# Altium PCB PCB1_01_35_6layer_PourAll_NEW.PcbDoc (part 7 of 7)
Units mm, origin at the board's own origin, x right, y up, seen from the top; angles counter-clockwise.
Board outline 26 x 17.5 mm, 6 copper layers (Top Layer, Layer 1, Layer 2, Layer 3, Layer 4, Bottom Layer), stack 0.816 mm thick; 0 components, 1 nets, 8 pads, 78 vias.

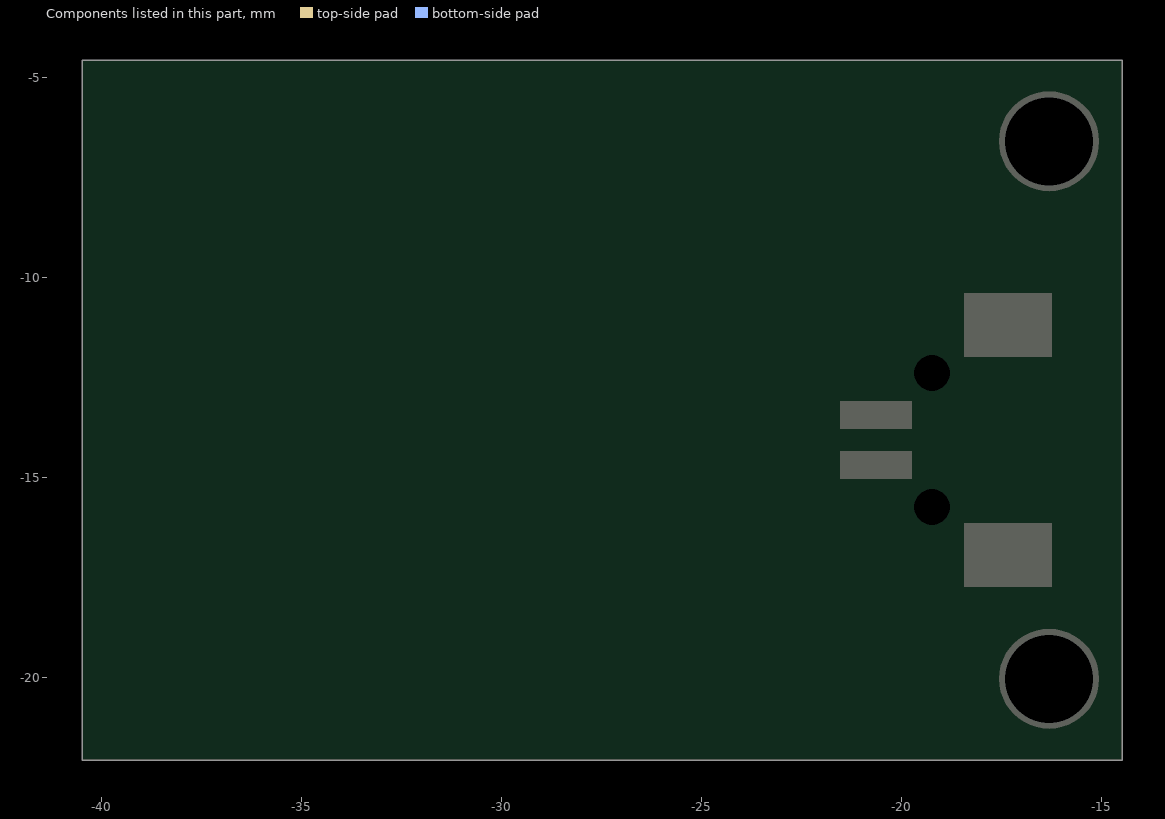
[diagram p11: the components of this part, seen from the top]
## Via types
v1: diameter 0.5, hole 0.3, Top Layer to Bottom Layer, tented both sides, 65 vias
v2: diameter 1, hole 0.5, Top Layer to Bottom Layer, 10 vias
v3: diameter 0.5, hole 0.25, Top Layer to Bottom Layer, 3 vias

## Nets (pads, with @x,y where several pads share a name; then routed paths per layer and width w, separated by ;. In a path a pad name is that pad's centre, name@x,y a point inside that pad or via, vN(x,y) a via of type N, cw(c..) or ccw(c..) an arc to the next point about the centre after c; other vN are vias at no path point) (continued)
copper on no net: (continued)
  Bottom Layer w0.1: -37.134,-9.58 cw(c-31.888,-13.205) -36.202,-8.509 cw(c-31.701,-13.403) -35.061,-7.666 cw(c-31.721,-13.359) -33.768,-7.084 cw(c-31.824,-13.032) -32.381,-6.799 cw(c-31.832,-13.115) -30.968,-6.834 cw(c-31.866,-13.39) -29.596,-7.174 cw(c-31.848,-13.355) -28.329,-7.797 cw(c-31.664,-13.071) -27.231,-8.68 cw(c-31.72,-13.105) -26.361,-9.787 cw(c-31.957,-13.256) -25.751,-11.055 cw(c-31.926,-13.25) -25.425,-12.422 cw(c-31.598,-13.212) -25.405,-13.825 cw(c-31.64,-13.192) -25.702,-15.195 cw(c-31.912,-13.104) -26.288,-16.467 cw(c-31.895,-13.12) -27.13,-17.585 cw(c-31.66,-13.344) -28.194,-18.491 cw(c-31.661,-13.315) -29.433,-19.133 cw(c-31.768,-13.045) -30.781,-19.49 cw(c-31.77,-13.061) -32.173,-19.553 cw(c-31.794,-13.377) -33.543,-19.312 cw(c-31.777,-13.377) -34.822,-18.769 cw(c-31.635,-13.119) -35.951,-17.962 cw(c-31.643,-13.121) -36.883,-16.934 cw(c-31.897,-13.301) -37.568,-15.73 cw(c-31.903,-13.32) -37.963,-14.405 cw(c-31.61,-13.264) -38.06,-13.026 cw(c-31.609,-13.26) -37.863,-11.659 cw(c-31.902,-13.181) -37.374,-10.37 cw(c-31.938,-13.18) -36.608,-9.226 cw(c-31.705,-13.373) -35.612,-8.276 cw(c-31.696,-13.377) -34.438,-7.56 cw(c-31.819,-13.107) -33.139,-7.117 cw(c-31.845,-13.061) -31.775,-6.978 cw(c-31.845,-13.366) -30.415,-7.14 cw(c-31.845,-13.384) -29.121,-7.587 cw(c-31.718,-13.123) -27.956,-8.301 cw(c-31.687,-13.059) -26.984,-9.259 cw(c-31.925,-13.256) -26.245,-10.406 cw(c-31.946,-13.271) -25.767,-11.682 cw(c-31.671,-13.204) -25.576,-13.028 cw(c-31.584,-13.187) -25.694,-14.382 cw(c-31.89,-13.128) -26.105,-15.676 cw(c-31.922,-13.119) -26.78,-16.853 cw(c-31.701,-13.284) -27.692,-17.854 cw(c-31.621,-13.354) -28.805,-18.622 cw(c-31.772,-13.078) -30.058,-19.128 cw(c-31.788,-13.041) -31.389,-19.357 cw(c-31.774,-13.309) -32.735,-19.292 cw(c-31.781,-13.432) -34.031,-18.927 cw(c-31.663,-13.137) -35.214,-18.286 cw(c-31.64,-13.096) -36.234,-17.41 cw(c-31.833,-13.271) -37.039,-16.337 cw(c-31.946,-13.353) -37.581,-15.111 cw(c-31.643,-13.255) -37.84,-13.797 cw(c-31.589,-13.246) -37.815,-12.459 cw(c-31.84,-13.21) -37.503,-11.161 cw(c-31.99,-13.169) -36.906,-9.967 cw(c-31.72,-13.341) -36.063,-8.935 cw(c-31.673,-13.382) -35.021,-8.105 cw(c-31.802,-13.172) -33.827,-7.521 cw(c-31.87,-13.016) -32.533,-7.221 cw(c-31.831,-13.334) -31.206,-7.212 cw(c-31.834,-13.403) -29.909,-7.486 cw(c-31.756,-13.177) -28.703,-8.031 cw(c-31.67,-13.012) -27.652,-8.832 cw(c-31.891,-13.246) -26.804,-9.845 cw(c-31.952,-13.292) -26.19,-11.013 cw(c-31.736,-13.21) -25.843,-12.284 cw(c-31.54,-13.17) -25.791,-13.599 cw(c-31.86,-13.148) -26.029,-14.892 cw(c-31.941,-13.128) -26.537,-16.103 cw(c-31.746,-13.24) -27.291,-17.176 cw(c-31.581,-13.375) -28.266,-18.05 cw(c-31.767,-13.115) -29.409,-18.687 cw(c-31.806,-13.033) -30.66,-19.067 cw(c-31.77,-13.247) -31.961,-19.169 cw(c-31.769,-13.473) -33.25,-18.976 cw(c-31.663,-13.102) -35.548,-17.785 cw(c-31.784,-13.236) -36.452,-16.852 cw(c-31.968,-13.387) -37.122,-15.741 cw(c-31.613,-13.232) -37.667,-13.223 cw(c-31.782,-13.225) -37.524,-11.938 cw(c-32.027,-13.176) -37.098,-10.719 cw(c-31.682,-13.351) -35.512,-8.704 cw(c-31.776,-13.225) -34.436,-7.998 cw(c-31.899,-12.995) -33.231,-7.552 cw(c-31.814,-13.372) -30.68,-7.49 cw(c-31.779,-13.23) -29.456,-7.868 cw(c-31.676,-12.98) -28.349,-8.508 cw(c-31.912,-13.284) -26.684,-10.426 cw(c-31.64,-13.165) -25.985,-12.858 cw(c-31.905,-13.156) -26.4,-15.352 cw(c-31.65,-13.286) -27.822,-17.431 cw(c-31.803,-13.082) -29.997,-18.694 cw(c-31.744,-13.352) -32.493,-18.922 cw(c-31.685,-13.115) -34.842,-18.056 cw(c-31.85,-13.324) -36.6,-16.287 cw(c-31.638,-13.225) -37.425,-13.937 cw(c-31.893,-13.229) -37.184,-11.466 cw(c-31.692,-13.327) -35.905,-9.343 cw(c-31.85,-13.14) -33.858,-7.96 cw(c-31.803,-13.348) -31.419,-7.594 cw(c-31.788,-13.277) -30.2,-7.808 cw(c-31.702,-12.979) -29.061,-8.287 cw(c-31.886,-13.276) -27.234,-9.925 cw(c-31.829,-13.249) -26.624,-10.995 cw(c-31.544,-13.126) -26.268,-12.173 cw(c-31.881,-13.171) -26.366,-14.612 cw(c-31.835,-13.194) -26.8,-15.758 cw(c-31.556,-13.337) -27.477,-16.778 cw(c-31.799,-13.11) -29.409,-18.25 cw(c-31.792,-13.153) -30.563,-18.644 cw(c-31.724,-13.458) -31.774,-18.772 cw(c-31.704,-13.137) -34.128,-18.225 cw(c-31.728,-13.16) -35.162,-17.59 cw(c-31.92,-13.406) -36.028,-16.743 cw(c-31.667,-13.225) -37.101,-14.591 cw(c-31.691,-13.218) -37.269,-13.395 cw(c-32.002,-13.227) -37.17,-12.194 cw(c-31.712,-13.305) -36.201,-10.007 cw(c-31.714,-13.288) -35.391,-9.12 cw(c-31.917,-13.055) -34.407,-8.434 cw(c-31.841,-13.214) -33.296,-7.987 cw(c-31.785,-13.4) -32.116,-7.79 cw(c-31.786,-13.316) -30.922,-7.848 cw(c-31.736,-13.013) -29.772,-8.167 cw(c-31.806,-13.16) -28.726,-8.736 cw(c-31.916,-13.324) -27.826,-9.516 cw(c-31.857,-13.275) -27.114,-10.468 cw(c-31.594,-13.122) -26.629,-11.551 cw(c-31.738,-13.157) -26.401,-12.714 cw(c-31.94,-13.177) -26.429,-13.899 cw(c-31.871,-13.19) -26.707,-15.048 cw(c-31.589,-13.294) -27.23,-16.107 cw(c-31.695,-13.214) -27.977,-17.019 cw(c-31.842,-13.068) -28.902,-17.749 cw(c-31.812,-13.123) -29.96,-18.264 cw(c-31.714,-13.403) -31.103,-18.535 cw(c-31.717,-13.286) -32.276,-18.541 cw(c-31.698,-13.075) -33.422,-18.294 cw(c-31.719,-13.127) -34.487,-17.81 cw(c-31.87,-13.377) -35.42,-17.106 cw(c-31.791,-13.311) -36.168,-16.211 cw(c-31.614,-13.19) -36.705,-15.176 cw(c-31.661,-13.204) -37.01,-14.052 cw(c-31.945,-13.246) -37.061,-12.891 cw(c-31.86,-13.264) -36.85,-11.75 cw(c-31.649,-13.325) -36.397,-10.682 cw(c-31.684,-13.301) -35.729,-9.736 cw(c-31.895,-13.112) -34.872,-8.96 cw(c-31.863,-13.176) -33.863,-8.398 cw(c-31.774,-13.381) -32.757,-8.068 cw(c-31.777,-13.346) -31.609,-7.981 cw(c-31.766,-13.068) -30.47,-8.146 cw(c-31.792,-13.118) -29.4,-8.563 cw(c-31.894,-13.32) -28.447,-9.201 cw(c-31.873,-13.301) -27.651,-10.026 cw(c-31.656,-13.136) -27.056,-11.003 cw(c-31.697,-13.141) -26.697,-12.087 cw(c-31.921,-13.191) -26.582,-13.223 cw(c-31.9,-13.195) -26.71,-14.356 cw(c-31.64,-13.256) -27.082,-15.431 cw(c-31.656,-13.234) -27.685,-16.394 cw(c-31.84,-13.092) -28.482,-17.202 cw(c-31.833,-13.105) -29.432,-17.822 cw(c-31.717,-13.339) -30.491,-18.219 cw(c-31.707,-13.329) -31.611,-18.367 cw(c-31.714,-13.092) -32.736,-18.268 cw(c-31.72,-13.1) -33.813,-17.933 cw(c-31.824,-13.333) -34.789,-17.373 cw(c-31.818,-13.347) -35.613,-16.609 cw(c-31.638,-13.189) -36.25,-15.684 cw(c-31.642,-13.186) -36.676,-14.647 cw(c-31.882,-13.253) -36.866,-13.544 cw(c-31.904,-13.267) -36.802,-12.428 cw(c-31.665,-13.305) -36.497,-11.353 cw(c-31.659,-13.303) -35.972,-10.369 cw(c-31.859,-13.164) -35.247,-9.524 cw(c-31.894,-13.145) -34.352,-8.866 cw(c-31.77,-13.356) -33.335,-8.419 cw(c-31.763,-13.365) -32.248,-8.197 cw(c-31.782,-13.128) -31.142,-8.217 cw(c-31.788,-13.074) -30.069,-8.486 cw(c-31.872,-13.307) -29.082,-8.981 cw(c-31.878,-13.323) -28.224,-9.674 cw(c-31.712,-13.161) -27.537,-10.534 cw(c-31.661,-13.115) -27.063,-11.526 cw(c-31.896,-13.199) -26.817,-12.597 cw(c-31.919,-13.206) -26.804,-13.694 cw(c-31.695,-13.23) -27.028,-14.765 cw(c-31.613,-13.245) -27.488,-15.757 cw(c-31.83,-13.116) -28.152,-16.624 cw(c-31.853,-13.099) -28.984,-17.329 cw(c-31.733,-13.282) -29.947,-17.837 cw(c-31.688,-13.367) -30.999,-18.114 cw(c-31.726,-13.117) -32.084,-18.154 cw(c-31.727,-13.081) -33.152,-17.963 cw(c-31.79,-13.285) -34.151,-17.547 cw(c-31.834,-13.386) -35.03,-16.917 cw(c-31.665,-13.195) -35.748,-16.111 cw(c-31.633,-13.169) -36.278,-15.172 cw(c-31.825,-13.248) -36.593,-14.142 cw(c-31.943,-13.28) -36.667,-13.07 cw(c-31.688,-13.289) -36.505,-12.009 cw(c-31.641,-13.298) -36.121,-11.007 cw(c-31.819,-13.204) -35.532,-10.114 cw(c-31.929,-13.124) -34.758,-9.377 cw(c-31.773,-13.327) -33.842,-8.829 cw(c-31.747,-13.374) -32.832,-8.488 cw(c-31.787,-13.183) -31.774,-8.374 cw(c-31.795,-13.036) -30.719,-8.499 cw(c-31.852,-13.286) -29.718,-8.854 cw(c-31.874,-13.34) -28.817,-9.412 cw(c-31.756,-13.193) -28.059,-10.15 cw(c-31.639,-13.086) -27.486,-11.038 cw(c-31.867,-13.201) -27.124,-12.029 cw(c-31.929,-13.22) -26.981,-13.073 cw(c-31.746,-13.217) -27.065,-14.122 cw(c-31.578,-13.242) -27.383,-15.123 cw(c-31.812,-13.139) -27.912,-16.028 cw(c-31.869,-13.101) -28.622,-16.8 cw(c-31.755,-13.236) -29.478,-17.399 cw(c-31.663,-13.39) -30.446,-17.791 cw(c-31.732,-13.146) -31.475,-17.959 cw(c-31.74,-13.071) -32.516,-17.904 cw(c-31.77,-13.239) -33.518,-17.628 cw(c-31.834,-13.417) -34.431,-17.135 cw(c-31.655,-13.168) -35.829,-15.621 cw(c-31.778,-13.234) -36.253,-14.678 cw(c-31.965,-13.3) -36.454,-13.666 cw(c-31.659,-13.28) -36.18,-11.636 cw(c-31.779,-13.23) -35.726,-10.715 cw(c-31.956,-13.123) -35.079,-9.919 cw(c-31.746,-13.346) -33.35,-8.843 cw(c-31.781,-13.229) -32.357,-8.607 cw(c-31.811,-13.018) -31.337,-8.599 cw(c-31.85,-13.32) -29.418,-9.241 cw(c-31.71,-13.124) -27.955,-10.627 cw(c-31.894,-13.224) -27.232,-12.504 cw(c-31.662,-13.209) -27.367,-14.503 ; -37.134,-9.58 ccw(c-31.963,-13.136) -37.802,-10.836 ccw(c-31.639,-13.267) -38.179,-12.209 ccw(c-31.585,-13.281) -38.256,-13.632 ccw(c-31.851,-13.299) -38.024,-15.039 ccw(c-31.971,-13.318) -37.48,-16.359 ccw(c-31.659,-13.15) -36.659,-17.53 ccw(c-31.607,-13.111) -35.607,-18.501 ccw(c-31.76,-13.323) -34.37,-19.222 ccw(c-31.828,-13.445) -33,-19.647 ccw(c-31.758,-13.093) -31.569,-19.761 ccw(c-31.756,-13.02) -30.144,-19.568 ccw(c-31.691,-13.267) -28.794,-19.072 ccw(c-31.631,-13.414) -27.588,-18.284 ccw(c-31.862,-13.132) -26.584,-17.249 ccw(c-31.923,-13.078) -25.821,-16.023 ccw(c-31.695,-13.184) -25.34,-14.661 ccw(c-31.526,-13.235) -25.178,-13.224 ccw(c-31.894,-13.233) -25.336,-11.784 ccw(c-31.983,-13.247) -25.797,-10.409 ccw(c-31.762,-13.142) -26.543,-9.165 ccw(c-31.601,-13.033) -27.551,-8.12 ccw(c-31.84,-13.318) -28.766,-7.321 ccw(c-31.889,-13.403) -30.125,-6.797 ccw(c-31.831,-13.171) -31.565,-6.578 ccw(c-31.812,-12.96) -33.02,-6.688 ccw(c-31.744,-13.328) -34.416,-7.117 ccw(c-31.706,-13.428) -35.691,-7.834 ccw(c-31.845,-13.241) -36.782,-8.808 ccw(c-32.009,-13.082) -37.628,-10.004 ccw(c-31.68,-13.264) -38.19,-11.359 ccw(c-31.665,-13.284) -38.395,-14.272 ccw(c-32.04,-13.317) -38.012,-15.692 ccw(c-31.688,-13.179) -37.323,-16.994 ccw(c-31.653,-13.173) -35.201,-19.018 ccw(c-31.873,-13.495) -33.856,-19.63 ccw(c-31.755,-13.135) -32.408,-19.93 ccw(c-31.737,-13.092) -29.484,-19.583 ccw(c-31.624,-13.478) -28.15,-18.936 ccw(c-31.826,-13.158) -26.991,-18.007 ccw(c-31.856,-13.108) -25.387,-15.522 ccw(c-31.476,-13.27) -25.034,-14.075 ccw(c-31.85,-13.223) -25.011,-12.584 ccw(c-31.92,-13.216) -25.908,-9.753 ccw(c-31.545,-13.02) -26.801,-8.554 ccw(c-31.818,-13.276) -27.939,-7.582 ccw(c-31.875,-13.336) -30.704,-6.464 ccw(c-31.795,-13.092) -33.684,-6.646 ccw(c-31.748,-13.377) -36.318,-8.069 ccw(c-31.896,-13.152) -38.085,-10.491 ccw(c-31.633,-13.302) -38.67,-13.44 ccw(c-31.914,-13.274) -37.927,-16.358 ccw(c-31.62,-13.161) -36.019,-18.697 ccw(c-31.827,-13.371) -33.287,-19.99 ccw(c-31.724,-13.06) -30.256,-20.01 ccw(c-31.69,-13.365) -27.508,-18.724 ccw(c-31.872,-13.078) -25.552,-16.393 ccw(c-31.604,-13.251) -24.788,-13.444 ccw(c-31.952,-13.208) -25.34,-10.438 ccw(c-31.639,-13.104) -27.132,-7.96 ccw(c-31.901,-13.355) -29.811,-6.464 ccw(c-31.757,-12.911) -31.331,-6.19 ccw(c-31.77,-13.226) -32.875,-6.264 ccw(c-31.751,-13.409) -35.746,-7.38 ccw(c-32.003,-13.015) -36.931,-8.38 ccw(c-31.777,-13.216) -37.862,-9.622 ccw(c-31.612,-13.325) -38.836,-12.556 ccw(c-32.076,-13.268) -38.821,-14.113 ccw(c-31.791,-13.224) -38.457,-15.628 ccw(c-31.59,-13.16) -36.809,-18.26 ccw(c-31.928,-13.482) -35.595,-19.244 ccw(c-31.788,-13.245) -34.19,-19.932 ccw(c-31.697,-13.005) -32.667,-20.302 ccw(c-31.707,-13.117) -31.1,-20.341 ccw(c-31.673,-13.501) -29.562,-20.032 ccw(c-31.762,-13.257) -28.131,-19.385 ccw(c-31.893,-13.027) -26.87,-18.444 ccw(c-31.819,-13.099) -25.837,-17.257 ccw(c-31.501,-13.318) -25.091,-15.869 ccw(c-31.731,-13.239) -24.676,-14.348 ccw(c-32,-13.191) -24.597,-12.771 ccw(c-31.906,-13.181) -24.855,-11.212 ccw(c-31.534,-13.074) -25.451,-9.747 ccw(c-31.726,-13.194) -26.361,-8.453 ccw(c-31.941,-13.377) -27.531,-7.383 ccw(c-31.894,-13.304) -28.902,-6.585 ccw(c-31.739,-12.95) -30.417,-6.108 ccw(c-31.766,-13.157) -32,-5.984 ccw(c-31.761,-13.448) -33.577,-6.204 ccw(c-31.785,-13.374) -35.071,-6.755 ccw(c-31.959,-13.03) -36.409,-7.62 ccw(c-31.827,-13.168) -37.519,-8.766 ccw(c-31.593,-13.355) -38.357,-10.126 ccw(c-31.658,-13.329) -38.887,-11.634 ccw(c-32.032,-13.245) -39.074,-13.223 ccw(c-31.861,-13.23) -38.898,-14.814 ccw(c-31.56,-13.167) -38.381,-16.333 ccw(c-31.613,-13.198) -37.554,-17.708 ccw(c-31.914,-13.431) -36.445,-18.869 ccw(c-31.83,-13.305) -35.101,-19.751 ccw(c-31.683,-13.025) -33.597,-20.324 ccw(c-31.691,-13.076) -32.003,-20.563 ccw(c-31.703,-13.454) -30.396,-20.449 ccw(c-31.743,-13.329) -28.854,-19.974 ccw(c-31.868,-13.029) -27.448,-19.176 ccw(c-31.839,-13.061) -26.244,-18.097 ccw(c-31.558,-13.308) -25.303,-16.78 ccw(c-31.662,-13.271) -24.684,-15.284 ccw(c-31.981,-13.174) -24.402,-13.687 ccw(c-31.947,-13.171) -24.466,-12.065 ccw(c-31.581,-13.113) -24.883,-10.495 ccw(c-31.656,-13.161) -25.643,-9.058 ccw(c-31.941,-13.35) -26.699,-7.818 ccw(c-31.928,-13.329) -27.994,-6.83 ccw(c-31.741,-13.013) -29.475,-6.147 ccw(c-31.745,-13.082) -31.073,-5.816 ccw(c-31.781,-13.429) -32.707,-5.84 ccw(c-31.789,-13.415) -34.3,-6.209 ccw(c-31.911,-13.074) -35.775,-6.918 ccw(c-31.872,-13.102) -37.054,-7.942 ccw(c-31.622,-13.357) -38.081,-9.221 ccw(c-31.63,-13.359) -38.815,-10.69 ccw(c-31.966,-13.238) -39.211,-12.284 ccw(c-31.942,-13.222) -39.237,-13.928 ccw(c-31.578,-13.191) -38.905,-15.54 ccw(c-31.573,-13.195) -38.238,-17.047 ccw(c-31.876,-13.375) -37.259,-18.374 ccw(c-31.89,-13.362) -36.004,-19.446 ccw(c-31.677,-13.055) -34.544,-20.221 ccw(c-31.667,-13.045) -32.952,-20.669 ccw(c-31.72,-13.388) -31.3,-20.76 ccw(c-31.738,-13.413) -29.668,-20.476 ccw(c-31.841,-13.046) -28.135,-19.843 ccw(c-31.847,-13.023) -26.769,-18.898 ccw(c-31.62,-13.279) -25.642,-17.679 ccw(c-31.593,-13.321) -24.817,-16.235 ccw(c-31.949,-13.164) -24.326,-14.644 ccw(c-31.98,-13.152) -24.184,-12.983 ccw(c-31.644,-13.141) -24.405,-11.331 ccw(c-31.572,-13.141) -24.994,-9.77 ccw(c-31.926,-13.318) -25.91,-8.372 ccw(c-31.963,-13.341) -27.104,-7.2 ccw(c-31.761,-13.079) -28.523,-6.314 ccw(c-31.705,-13.003) -30.107,-5.77 ccw(c-31.796,-13.396) -31.774,-5.585 ccw(c-31.802,-13.449) -33.444,-5.758 ccw(c-31.874,-13.132) -35.037,-6.289 ccw(c-31.907,-13.02) -36.471,-7.166 ccw(c-31.658,-13.346) -37.681,-8.337 ccw(c-31.614,-13.39) -38.615,-9.739 ccw(c-31.898,-13.247) -39.224,-11.31 ccw(c-32.027,-13.196) -39.464,-12.981 ccw(c-31.611,-13.212) -39.332,-14.665 ccw(c-31.539,-13.204) -38.845,-16.284 ccw(c-31.825,-13.33) -38.019,-17.761 ccw(c-31.964,-13.41) -36.881,-19.015 ccw(c-31.683,-13.095) -35.494,-19.99 ccw(c-31.639,-13.026) -33.93,-20.649 ccw(c-31.722,-13.32) -32.26,-20.956 ccw(c-31.75,-13.5) -30.563,-20.878 ccw(c-31.814,-13.078) -28.921,-20.429 ccw(c-31.843,-12.99) -27.411,-19.641 ccw(c-31.673,-13.237) -26.106,-18.546 ccw(c-31.535,-13.387) -25.079,-17.184 ccw(c-31.906,-13.165) -24.377,-15.627 ccw(c-32.001,-13.128) -24.02,-13.955 ccw(c-31.71,-13.153) -24.032,-12.245 ccw(c-31.486,-13.14) -24.429,-10.58 ccw(c-31.897,-13.286) -25.183,-9.041 ccw(c-31.994,-13.341) -26.248,-7.696 ccw(c-31.794,-13.137) -27.578,-6.611 ccw(c-31.651,-12.938) -29.119,-5.852 ccw(c-31.802,-13.351) -30.792,-5.451 ccw(c-31.823,-13.471) -32.513,-5.414 ccw(c-31.852,-13.194) -34.203,-5.749 ccw(c-31.92,-12.939) -35.776,-6.455 ccw(c-31.697,-13.32) -37.156,-7.492 ccw(c-31.698,-13.345) -39.107,-10.32 ccw(c-32.095,-13.154) -39.568,-11.988 ccw(c-31.658,-13.224) -39.649,-13.718 ccw(c-31.625,-13.24) -38.71,-17.037 ccw(c-32.038,-13.433) -37.715,-18.46 ccw(c-31.705,-13.14) -36.429,-19.629 ccw(c-31.664,-13.113) -33.262,-21.025 ccw(c-31.78,-13.568) -31.525,-21.167 ccw(c-31.794,-13.125) -29.798,-20.92 ccw(c-31.793,-13.062) -26.693,-19.364 ccw(c-31.54,-13.414) -25.472,-18.112 ccw(c-31.788,-13.218) -24.566,-16.637 -24.409,-16.48 -23.754,-16.48 v2(-23.012,-17.221) ; v3(-32.283,-13.538) -32.283,-14.234 ccw(c-31.771,-13.346) -32.128,-14.307 ; -32.125,-14.306 ccw(c-31.756,-13.314) -31.882,-14.365 ccw(c-31.755,-13.283) -31.63,-14.365 ccw(c-31.766,-13.186) -31.383,-14.309 ccw(c-31.782,-13.137) -31.151,-14.203 ccw(c-31.773,-13.151) -30.945,-14.05 ccw(c-31.725,-13.201) -30.776,-13.856 ccw(c-31.694,-13.228) -30.592,-13.373 ccw(c-31.83,-13.203) -30.584,-13.11 ccw(c-31.849,-13.202) -30.73,-12.604 ccw(c-31.759,-13.156) -30.882,-12.385 ccw(c-31.725,-13.129) -31.083,-12.207 ccw(c-31.784,-13.214) -31.32,-12.078 ccw(c-31.816,-13.289) -31.581,-12.001 ccw(c-31.819,-13.302) -31.854,-11.98 ccw(c-31.821,-13.246) -32.126,-12.017 ccw(c-31.842,-13.163) -32.384,-12.114 ccw(c-31.835,-13.168) -32.614,-12.27 ccw(c-31.764,-13.251) -32.804,-12.475 ccw(c-31.712,-13.291) -32.948,-12.716 ccw(c-31.72,-13.288) -33.04,-12.983 ccw(c-31.791,-13.272) -33.073,-13.265 ccw(c-31.877,-13.272) -33.041,-13.548 ccw(c-31.816,-13.254) -32.942,-13.818 ccw(c-31.722,-13.208) -32.787,-14.061 ccw(c-31.693,-13.187) -32.34,-14.429 ccw(c-31.743,-13.28) -32.067,-14.533 ccw(c-31.761,-13.345) -31.774,-14.572 ccw(c-31.76,-13.24) -31.48,-14.542 ccw(c-31.78,-13.147) -31.196,-14.45 ccw(c-31.789,-13.123) -30.937,-14.3 ccw(c-31.757,-13.166) -30.714,-14.099 ccw(c-31.686,-13.228) -30.54,-13.852 ccw(c-31.67,-13.241) -30.428,-13.569 ccw(c-31.786,-13.21) -30.383,-13.268 ccw(c-31.867,-13.206) -30.402,-12.961 ccw(c-31.868,-13.205) -30.484,-12.663 ccw(c-31.801,-13.178) -30.627,-12.389 ccw(c-31.719,-13.123) -30.83,-12.153 ccw(c-31.745,-13.157) -31.084,-11.97 ccw(c-31.803,-13.259) -31.374,-11.847 ccw(c-31.821,-13.318) -31.685,-11.787 ccw(c-31.82,-13.294) -32.002,-11.792 ccw(c-31.832,-13.206) -32.312,-11.865 ccw(c-31.843,-13.158) -32.845,-12.216 ccw(c-31.727,-13.279) -33.043,-12.473 ccw(c-31.712,-13.291) -33.26,-13.084 ccw(c-31.84,-13.272) -33.266,-13.412 ccw(c-31.89,-13.274) -33.194,-13.734 ccw(c-31.771,-13.232) -33.05,-14.032 ccw(c-31.689,-13.182) -32.845,-14.295 ccw(c-31.678,-13.174) -32.589,-14.511 ccw(c-31.718,-13.233) -32.293,-14.669 ccw(c-31.757,-13.333) -31.968,-14.757 ccw(c-31.76,-13.318) -31.629,-14.766 ccw(c-31.771,-13.189) -31.295,-14.699 ccw(c-31.793,-13.114) -30.98,-14.563 ccw(c-31.785,-13.126) -30.7,-14.365 ccw(c-31.725,-13.194) -30.467,-14.11 ccw(c-31.639,-13.256) -30.298,-13.808 ccw(c-31.715,-13.229) -30.204,-13.473 ccw(c-31.838,-13.208) -30.185,-13.123 ccw(c-31.877,-13.207) -30.363,-12.446 ccw(c-31.758,-13.149) -30.557,-12.15 ccw(c-31.696,-13.1) -30.816,-11.906 ccw(c-31.771,-13.203) -31.126,-11.727 ccw(c-31.817,-13.305) -31.468,-11.618 ccw(c-31.824,-13.331) -31.827,-11.582 ccw(c-31.825,-13.264) -32.187,-11.621 ccw(c-31.85,-13.151) -32.53,-11.74 ccw(c-31.854,-13.132) -32.837,-11.937 ccw(c-31.765,-13.242) -33.093,-12.199 ccw(c-31.692,-13.301) -33.29,-12.511 ccw(c-31.694,-13.301) -33.419,-12.858 ccw(c-31.782,-13.28) -33.472,-13.224 ccw(c-31.901,-13.276) -33.44,-13.595 ccw(c-31.848,-13.26) -33.321,-13.95 ccw(c-31.722,-13.202) -33.126,-14.272 ccw(c-31.666,-13.161) -32.868,-14.547 ccw(c-31.685,-13.185) -32.557,-14.764 ccw(c-31.737,-13.281) -32.206,-14.91 ccw(c-31.759,-13.332) -31.447,-14.942 ccw(c-31.787,-13.137) -31.078,-14.831 ccw(c-31.79,-13.119) -30.443,-14.394 ccw(c-31.677,-13.23) -30.211,-14.082 ccw(c-31.632,-13.26) -30.057,-13.723 ccw(c-31.775,-13.218) -29.988,-13.337 ccw(c-31.885,-13.209) -30.003,-12.942 ccw(c-31.898,-13.21) -30.098,-12.558 ccw(c-31.816,-13.179) -30.273,-12.201 ccw(c-31.707,-13.109) -30.524,-11.892 ccw(c-31.719,-13.129) -30.842,-11.65 ccw(c-31.797,-13.259) -31.208,-11.483 ccw(c-31.826,-13.342) -31.602,-11.396 ccw(c-31.825,-13.322) -32.008,-11.392 ccw(c-31.836,-13.214) -32.405,-11.474 ccw(c-31.875,-13.094) -32.774,-11.646 ccw(c-31.819,-13.177) -33.095,-11.901 ccw(c-31.719,-13.279) -33.353,-12.221 ccw(c-31.687,-13.304) -33.649,-12.988 ccw(c-31.843,-13.277) -33.668,-13.403 ccw(c-31.932,-13.28) -33.589,-13.812 ccw(c-31.79,-13.234) -33.418,-14.194 ccw(c-31.679,-13.17) -33.167,-14.532 ccw(c-31.657,-13.152) -32.852,-14.813 ccw(c-31.703,-13.219) -32.484,-15.022 ccw(c-31.758,-13.345) -32.078,-15.144 ccw(c-31.766,-13.36) -31.653,-15.168 ccw(c-31.775,-13.197) -31.231,-15.095 ccw(c-31.803,-13.095) -30.832,-14.935 ccw(c-31.799,-13.099) -30.473,-14.695 ccw(c-31.73,-13.181) -30.173,-14.385 ; -30.173,-14.385 ccw(c-31.618,-13.267) -29.951,-14.012 ccw(c-31.685,-13.243) -29.821,-13.597 ccw(c-31.84,-13.213) -29.785,-13.161 ccw(c-31.906,-13.211) -29.986,-12.31 ccw(c-31.764,-13.147) -30.217,-11.935 ccw(c-31.712,-13.117) -30.909,-11.389 ccw(c-31.817,-13.316) -31.331,-11.242 ccw(c-31.825,-13.331) -32.223,-11.221 ccw(c-31.856,-13.146) -32.653,-11.356 ccw(c-31.854,-13.135) -33.042,-11.588 ccw(c-31.762,-13.257) -33.37,-11.902 ccw(c-31.72,-13.297) -33.798,-12.704 ccw(c-31.865,-13.253) -33.872,-13.157 ccw(c-31.855,-13.248) -33.84,-13.617 ccw(c-31.715,-13.223) -33.707,-14.06 ccw(c-31.692,-13.218) -33.179,-14.818 ccw(c-31.811,-13.341) -32.802,-15.093 ccw(c-31.78,-13.275) -32.371,-15.275 ccw(c-31.741,-13.151) -31.908,-15.36 ccw(c-31.738,-13.126) -31.437,-15.346 ccw(c-31.725,-13.212) -30.978,-15.232 ccw(c-31.705,-13.285) -30.192,-14.71 ccw(c-31.834,-13.149) -29.901,-14.331 ccw(c-31.833,-13.148) -29.695,-13.898 ccw(c-31.732,-13.182) -29.587,-13.43 ccw(c-31.637,-13.195) -29.589,-12.948 ccw(c-31.789,-13.214) -29.699,-12.477 ccw(c-31.879,-13.244) -29.907,-12.038 ccw(c-31.858,-13.229) -30.204,-11.652 ccw(c-31.769,-13.143) -30.578,-11.339 ccw(c-31.742,-13.111) -31.016,-11.119 ccw(c-31.797,-13.26) -31.493,-11.001 ccw(c-31.808,-13.312) -32.472,-11.077 ccw(c-31.854,-13.149) -32.928,-11.272 ccw(c-31.835,-13.168) -33.328,-11.568 ccw(c-31.734,-13.278) -33.655,-11.945 ccw(c-31.724,-13.291) -34.039,-12.865 ccw(c-31.909,-13.253) -34.071,-13.368 ccw(c-31.817,-13.244) -33.987,-13.866 ccw(c-31.686,-13.208) -33.797,-14.336 ccw(c-31.667,-13.2) -33.512,-14.757 ccw(c-31.742,-13.265) -33.143,-15.108 ccw(c-31.79,-13.315) -32.213,-15.52 ccw(c-31.742,-13.123) -31.7,-15.566 ccw(c-31.74,-13.13) -31.188,-15.502 ccw(c-31.712,-13.246) -30.7,-15.33 ccw(c-31.675,-13.329) -30.263,-15.05 ccw(c-31.781,-13.2) -29.899,-14.678 ccw(c-31.855,-13.14) -29.621,-14.235 ccw(c-31.823,-13.154) -29.442,-13.743 ccw(c-31.69,-13.186) -29.374,-13.223 ccw(c-31.662,-13.192) -29.428,-12.699 ccw(c-31.826,-13.227) -29.596,-12.199 ccw(c-31.871,-13.243) -30.229,-11.354 ccw(c-31.745,-13.103) -30.668,-11.054 ccw(c-31.76,-13.146) -31.167,-10.862 ccw(c-31.8,-13.296) -31.697,-10.783 ccw(c-31.804,-13.34) -32.234,-10.817 ccw(c-31.82,-13.253) -32.752,-10.965 ccw(c-31.878,-13.112) -33.225,-11.225 ccw(c-31.809,-13.201) -33.628,-11.588 ccw(c-31.706,-13.295) -33.944,-12.031 ccw(c-31.694,-13.304) -34.161,-12.531 ccw(c-31.801,-13.272) -34.266,-13.067 ccw(c-31.86,-13.257) -34.104,-14.145 ccw(c-31.663,-13.192) -33.851,-14.635 ccw(c-31.674,-13.202) -33.499,-15.062 ccw(c-31.767,-13.298) -33.063,-15.403 ccw(c-31.814,-13.366) -32.559,-15.637 ccw(c-31.758,-13.196) -32.013,-15.752 ccw(c-31.746,-13.101) -31.454,-15.749 ccw(c-31.74,-13.145) -30.907,-15.629 ccw(c-31.691,-13.287) -30.398,-15.391 ccw(c-31.691,-13.301) -29.956,-15.042 ccw(c-31.814,-13.176) -29.6,-14.603 ccw(c-31.844,-13.15) -29.201,-13.547 ccw(c-31.64,-13.184) -29.183,-12.978 ccw(c-31.705,-13.197) -29.296,-12.419 ccw(c-31.86,-13.245) -29.528,-11.895 ccw(c-31.894,-13.263) -29.867,-11.431 ccw(c-31.821,-13.194) -30.296,-11.048 ccw(c-31.727,-13.062) -30.803,-10.771 ccw(c-31.774,-13.189) -31.36,-10.616 ccw(c-31.799,-13.33) -31.94,-10.585 ccw(c-31.8,-13.338) -32.515,-10.676 ccw(c-31.834,-13.217) -33.058,-10.888 ccw(c-31.894,-13.099) -33.54,-11.219 ccw(c-31.776,-13.233) -33.936,-11.651 ccw(c-31.68,-13.306) -34.233,-12.16 ccw(c-31.702,-13.298) -34.416,-12.72 ccw(c-31.846,-13.269) -34.473,-13.308 ccw(c-31.918,-13.264) -34.395,-13.895 ccw(c-31.733,-13.218) -34.187,-14.452 ccw(c-31.664,-13.187) -33.444,-15.377 ccw(c-31.792,-13.341) -32.939,-15.699 ccw(c-31.796,-13.331) -32.372,-15.896 ccw(c-31.754,-13.153) -31.774,-15.965 ccw(c-31.748,-13.123) -30.597,-15.722 ccw(c-31.661,-13.331) -30.076,-15.413 ccw(c-31.72,-13.264) -29.638,-14.991 ccw(c-31.847,-13.156) -29.3,-14.484 ccw(c-31.876,-13.139) -29.076,-13.915 ccw(c-31.766,-13.168) -28.978,-13.311 ccw(c-31.663,-13.181) -29.198,-12.109 ccw(c-31.887,-13.264) -29.5,-11.571 ccw(c-31.888,-13.263) -29.909,-11.106 ccw(c-31.796,-13.159) -30.409,-10.74 ccw(c-31.729,-13.05) -30.981,-10.497 ccw(c-31.784,-13.236) -31.595,-10.388 ccw(c-31.794,-13.357) -32.22,-10.412 ccw(c-31.801,-13.324) -32.827,-10.567 ccw(c-31.858,-13.174) -33.387,-10.85 ccw(c-31.884,-13.122) -33.868,-11.256 ccw(c-31.738,-13.261) -34.248,-11.759 ccw(c-31.682,-13.3) -34.655,-12.952 ccw(c-31.901,-13.271) -34.655,-13.587 ccw(c-31.873,-13.26) -34.509,-14.207 ccw(c-31.694,-13.197) -34.23,-14.782 ccw(c-31.674,-13.192) -33.343,-15.697 ccw(c-31.814,-13.392) -32.769,-15.988 ccw(c-31.78,-13.284) -32.143,-16.14 ccw(c-31.757,-13.114) -31.497,-16.154 ccw(c-31.757,-13.087) -30.86,-16.031 ccw(c-31.718,-13.209) -30.264,-15.776 ccw(c-31.681,-13.295) -29.314,-14.896 ccw(c-31.879,-13.144) -29.004,-14.319 ccw(c-31.87,-13.145) -28.821,-13.689 ccw(c-31.719,-13.171) -28.778,-13.035 ccw(c-31.599,-13.17) -28.886,-12.385 ccw(c-31.799,-13.227) -29.138,-11.775 ccw(c-31.906,-13.283) -29.514,-11.23 ccw(c-31.874,-13.253) -29.997,-10.775 ccw(c-31.769,-13.112) -30.568,-10.436 ccw(c-31.746,-13.079) -31.203,-10.237 ccw(c-31.787,-13.285) -31.869,-10.182 ccw(c-31.79,-13.344) -33.165,-10.496 ccw(c-31.892,-13.126) -33.732,-10.856 ccw(c-31.852,-13.161) -34.202,-11.338 ccw(c-31.699,-13.282) -34.558,-11.913 ccw(c-31.65,-13.308) -34.785,-12.552 ccw(c-31.759,-13.284) -34.872,-13.224 ccw(c-31.955,-13.28) -34.806,-13.901 ccw(c-31.821,-13.246) -34.586,-14.546 ccw(c-31.662,-13.173) -34.232,-15.13 ccw(c-31.646,-13.164) -33.762,-15.629 ccw(c-31.737,-13.272) -33.196,-16.016 ccw(c-31.786,-13.338) -31.873,-16.363 ccw(c-31.763,-13.082) -31.184,-16.314 ccw(c-31.758,-13.099) -30.519,-16.12 ccw(c-31.693,-13.254) -29.911,-15.787 ccw(c-31.635,-13.346) -29.393,-15.323 ccw(c-31.801,-13.198) -28.992,-14.754 ccw(c-31.903,-13.139) -28.719,-14.11 ccw(c-31.85,-13.153) -28.587,-13.422 ccw(c-31.661,-13.167) -28.608,-12.722 ccw(c-31.64,-13.173) -28.791,-12.043 ccw(c-31.843,-13.252) -29.119,-11.419 ccw(c-31.887,-13.274) -30.131,-10.443 ccw(c-31.746,-13.055) -30.773,-10.142 ccw(c-31.763,-13.131) -31.468,-9.996 ccw(c-31.783,-13.33) -32.18,-10.005 ccw(c-31.78,-13.379) -32.877,-10.163 ccw(c-31.822,-13.261) -33.525,-10.466 ccw(c-31.928,-13.087) -34.089,-10.908 ccw(c-31.81,-13.2) -34.539,-11.467 ccw(c-31.662,-13.296) -34.859,-12.113 ccw(c-31.653,-13.302) -35.037,-12.812 ccw(c-31.808,-13.282) -35.061,-13.534 ccw(c-31.976,-13.292) -34.92,-14.245 ccw(c-31.769,-13.224) -34.622,-14.907 ccw(c-31.639,-13.151) -34.189,-15.492 ccw(c-31.659,-13.172) -33.642,-15.974 ccw(c-31.763,-13.322) -33.003,-16.327 ccw(c-31.805,-13.406) -32.298,-16.524 ccw(c-31.768,-13.176) -31.565,-16.559 ccw(c-31.769,-13.082) -30.153,-16.168 ccw(c-31.656,-13.304) -29.543,-15.753 ccw(c-31.666,-13.307) -29.044,-15.208 ccw(c-31.846,-13.174) -28.675,-14.565 ccw(c-31.878,-13.153) -28.378,-13.115 ccw(c-31.597,-13.155) -28.473,-12.376 ccw(c-31.697,-13.188) -28.736,-11.677 ccw(c-31.88,-13.279) -29.145,-11.049 ccw(c-31.913,-13.303) -29.679,-10.519 ccw(c-31.827,-13.193) -30.312,-10.116 ccw(c-31.735,-13.006) -31.023,-9.864 ccw(c-31.773,-13.19) -31.773,-9.781 ccw(c-31.775,-13.369) -32.526,-9.86 ccw(c-31.778,-13.37) -33.247,-10.096 ccw(c-31.849,-13.215) -33.901,-10.481 ccw(c-31.943,-13.084) -34.452,-11.007 ccw(c-31.762,-13.233) -34.871,-11.644 ccw(c-31.631,-13.303) -35.146,-12.358 ccw(c-31.671,-13.295) -35.266,-13.115 ccw(c-31.868,-13.287) -35.218,-13.88 ccw(c-31.944,-13.292) -34.995,-14.616 ccw(c-31.72,-13.196) -34.614,-15.286 ccw(c-31.649,-13.152) -33.473,-16.317 ccw(c-31.787,-13.384) -32.762,-16.624 ccw(c-31.788,-13.353) -31.997,-16.759 ccw(c-31.772,-13.124) -31.22,-16.724 ccw(c-31.768,-13.098) -29.769,-16.172 ccw(c-31.61,-13.352) -29.168,-15.671 ccw(c-31.712,-13.266) -28.696,-15.045 ccw(c-31.889,-13.158) -28.37,-14.329 ccw(c-31.92,-13.146) -28.201,-13.559 ccw(c-31.765,-13.16) -28.2,-12.771 ccw(c-31.645,-13.159) -28.726,-11.29 ccw(c-31.907,-13.307) -29.219,-10.668 ccw(c-31.902,-13.298) -29.833,-10.162 ccw(c-31.801,-13.141) -30.542,-9.8 ccw(c-31.743,-13.003) -31.317,-9.609 ccw(c-31.775,-13.251) -32.116,-9.596 ccw(c-31.764,-13.397) -32.902,-9.753 ccw(c-31.782,-13.347) -33.639,-10.073 ccw(c-31.889,-13.163) -34.289,-10.545 ccw(c-31.918,-13.117) -34.814,-11.156 ccw(c-31.71,-13.26) -35.193,-11.869 ccw(c-31.645,-13.293) -35.464,-13.457 ccw(c-31.937,-13.301) -35.336,-14.258 ccw(c-31.884,-13.275) -35.026,-15.01 ccw(c-31.678,-13.164) -34.558,-15.678 ccw(c-31.665,-13.164) -33.256,-16.651 ccw(c-31.802,-13.448) -32.476,-16.9 ccw(c-31.778,-13.288) -31.658,-16.965 ccw(c-31.782,-13.078) -30.842,-16.852 ccw(c-31.785,-13.055) -30.067,-16.57 ccw(c-31.708,-13.207) -29.37,-16.128 ccw(c-31.655,-13.297) -28.357,-14.832 ccw(c-31.927,-13.151) -28.084,-14.047 ccw(c-31.905,-13.153) -27.981,-13.222 ccw(c-31.703,-13.154) -28.059,-12.393 ccw(c-31.57,-13.133) -28.325,-11.601 ccw(c-31.809,-13.245) -28.762,-10.888 ccw(c-31.923,-13.331) -29.342,-10.282 ccw(c-31.883,-13.278) -30.037,-9.81 ccw(c-31.777,-13.076) -30.819,-9.502 ccw(c-31.76,-13.051) -31.652,-9.381 ccw(c-31.769,-13.31) -32.494,-9.446 ccw(c-31.765,-13.37) -34.047,-10.096 ccw(c-31.94,-13.11) -34.682,-10.659 ccw(c-31.868,-13.161) -35.171,-11.354 ccw(c-31.66,-13.278) -35.499,-12.141 ccw(c-31.604,-13.297) -35.655,-12.981 ccw(c-31.754,-13.288) -35.628,-13.835 ccw(c-31.997,-13.322) -35.411,-14.663 ccw(c-31.822,-13.248) -35.009,-15.42 ccw(c-31.646,-13.131) -34.453,-16.076 ccw(c-31.635,-13.123) -33.77,-16.602 ccw(c-31.73,-13.283) -32.991,-16.969 ccw(c-31.799,-13.476) -32.146,-17.151 ccw(c-31.776,-13.221) -31.281,-17.137 ccw(c-31.796,-13.044) -30.436,-16.938 ccw(c-31.782,-13.075) -29.65,-16.567 ccw(c-31.667,-13.26) -28.963,-16.034 ccw(c-31.591,-13.349) -28.415,-15.356 ccw(c-31.824,-13.2) -28.031,-14.572 ccw(c-31.927,-13.157) -27.794,-12.846 ccw(c-31.631,-13.138) -27.96,-11.984 ccw(c-31.627,-13.149) -28.32,-11.182 ccw(c-31.856,-13.283) -28.849,-10.477 ccw(c-31.895,-13.308) -30.29,-9.472 ccw(c-31.76,-13.002) -31.141,-9.228 ccw(c-31.77,-13.121) -32.027,-9.186 ccw(c-31.757,-13.362) -32.903,-9.337 ccw(c-31.746,-13.411) -33.729,-9.67 ccw(c-31.826,-13.266) -34.467,-10.17 ccw(c-31.988,-13.075) -35.074,-10.825 ccw(c-31.809,-13.2) -35.516,-11.602 ccw(c-31.615,-13.286) -35.783,-12.459 ccw(c-31.614,-13.29) -35.864,-13.354 ccw(c-31.817,-13.295) -35.752,-14.245 ccw(c-32.007,-13.336) -35.439,-15.09 ccw(c-31.762,-13.211) -34.943,-15.843 ccw(c-31.625,-13.101) -34.296,-16.476 ccw(c-31.652,-13.14) -33.53,-16.96 ccw(c-31.754,-13.351) -32.678,-17.266 ccw(c-31.771,-13.372) -31.774,-17.37 ccw(c-31.768,-13.137) -30.869,-17.274 ccw(c-31.775,-13.091) -30.002,-16.987 ccw(c-31.706,-13.237) -29.218,-16.519 ccw(c-31.656,-13.317) -28.557,-15.885 ccw(c-31.834,-13.166) -28.051,-15.12 ccw(c-31.879,-13.139) -27.718,-14.264 ccw(c-31.725,-13.178) -27.577,-13.355 ccw(c-31.62,-13.19) -27.645,-12.436 ccw(c-31.854,-13.233) -27.913,-11.553 ccw(c-31.907,-13.252) -28.364,-10.745 ccw(c-31.782,-13.16) -28.979,-10.053 ccw(c-31.698,-13.078) -29.735,-9.515 ccw(c-31.816,-13.288) -30.592,-9.157 ccw(c-31.836,-13.347) -31.508,-8.988 ccw(c-31.828,-13.195) -32.44,-9.021 ccw(c-31.84,-13.067) -33.342,-9.263 ccw(c-31.752,-13.293) -34.17,-9.698 ccw(c-31.716,-13.352) -34.888,-10.3 ccw(c-31.826,-13.25) -35.46,-11.043 ccw(c-31.942,-13.172) -35.852,-11.898 ccw(c-31.71,-13.25) -36.045,-12.819 ccw(c-31.698,-13.26) -35.83,-14.684 ccw(c-31.925,-13.323) -35.418,-15.535 ccw(c-31.716,-13.193) -34.828,-16.277 ccw(c-31.695,-13.185) -33.243,-17.305 ccw(c-31.793,-13.408) -32.319,-17.533 ccw(c-31.761,-13.163) -31.365,-17.55 ccw(c-31.754,-13.134) -29.551,-16.981 ccw(c-31.64,-13.359) -28.781,-16.411 ccw(c-31.809,-13.178) -28.156,-15.682 ccw(c-31.834,-13.15) -27.434,-13.91 ccw(c-31.579,-13.206) -27.382,-12.947 ccw(c-31.827,-13.221) -27.546,-11.995 ccw(c-31.872,-13.225) -28.457,-10.299 ccw(c-31.661,-13.059) -29.171,-9.641 ccw(c-31.807,-13.259) -30.014,-9.157 ccw(c-31.836,-13.304) -31.914,-8.775 ccw(c-31.83,-13.029) -32.882,-8.907 ccw(c-31.769,-13.266) -33.798,-9.25 ccw(c-31.749,-13.325) -35.312,-10.479 ccw(c-31.863,-13.203) -36.152,-12.244 ccw(c-31.676,-13.268) -36.171,-14.206 ccw(c-31.851,-13.282) -35.341,-15.99 ccw(c-31.675,-13.173) -33.832,-17.263 ccw(c-31.779,-13.326) -31.917,-17.764 ccw(c-31.75,-13.112) -29.962,-17.409 ccw(c-31.695,-13.297) -28.346,-16.246 ccw(c-31.848,-13.132) -27.367,-14.503
  other v2: -22.225,-17.247 -22.809,-15.011 -22.073,-11.151

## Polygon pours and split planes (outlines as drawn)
Net1 on Top Layer "NET1_L01_P002" (solid, pour order 2): -40.489,-4.952 -40.495,-4.57 -14.495,-4.57 -14.495,-22.07 -40.488,-22.07
Net1 on Layer 1 "NET1_L02_P006" (solid, pour order 6): -40.481,-4.953 -40.488,-4.572 -14.488,-4.572 -14.488,-22.072 -40.48,-22.072
Net1 on Layer 3 "NET1_L04_P008" (solid, pour order 8): -40.489,-4.952 -40.495,-4.57 -14.495,-4.57 -14.495,-22.07 -40.488,-22.07
Net1 on Layer 4 "NET1_L05_P009" (solid, pour order 9): -40.489,-4.952 -40.495,-4.57 -14.495,-4.57 -14.495,-22.07 -40.488,-22.07
Net1 on Bottom Layer "NET1_L06_P010" (solid, pour order 10): -40.489,-4.952 -40.495,-4.57 -14.495,-4.57 -14.495,-22.07 -40.488,-22.07
Net1 on Layer 2 "NET1_L03_P007" (solid, pour order 7): -40.481,-4.953 -40.488,-4.572 -14.488,-4.572 -14.488,-22.072 -40.48,-22.072

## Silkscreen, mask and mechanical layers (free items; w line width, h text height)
Top Overlay:
  lines w0.2: -19.848,-16.472 -19.848,-16.897 -18.848,-16.897 ; -19.848,-11.672 -19.848,-11.247 -18.848,-11.247 ; -15.598,-16.897 -14.848,-16.897 -14.848,-11.247 -15.598,-11.247
  text "TYP-B 6-LAYER 35-COILS" at -25.092,-21.311 h0.6
Mechanical 2:
  the board outline again, w0.254
Mechanical 13:
  lines w0.1: -19.848,-16.897 -14.848,-16.897 -14.848,-11.247 -19.848,-11.247 -19.848,-16.897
